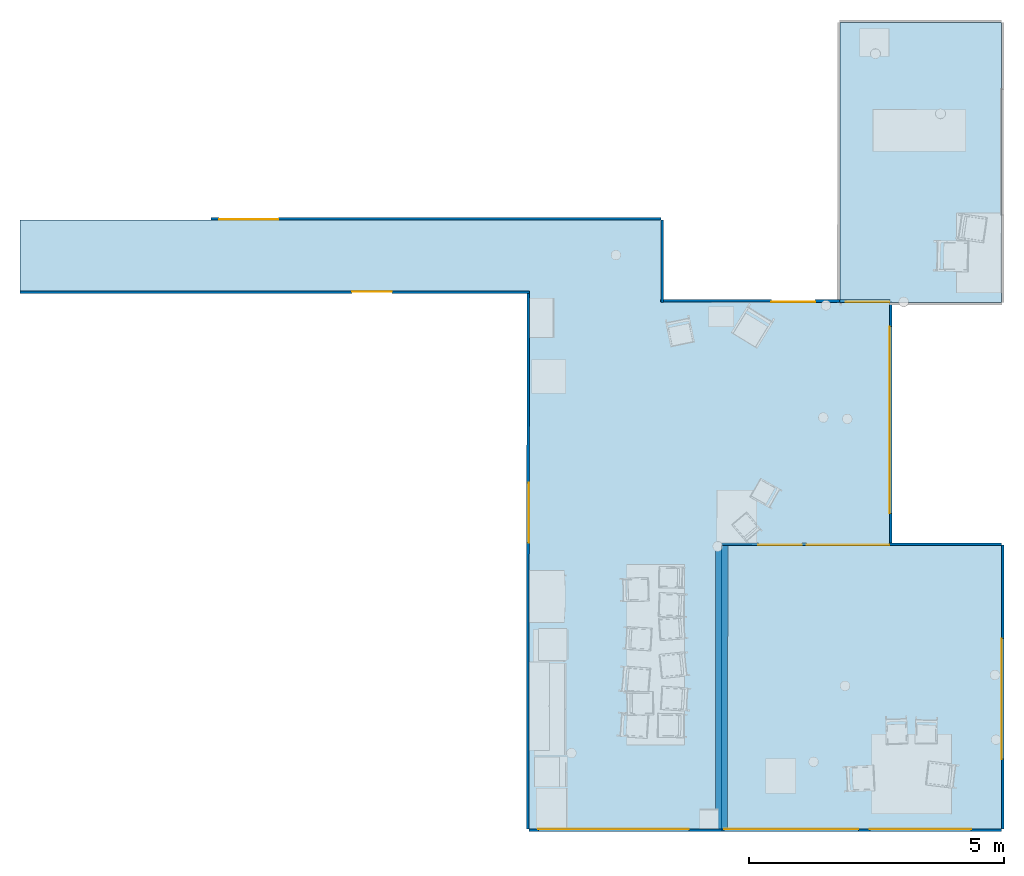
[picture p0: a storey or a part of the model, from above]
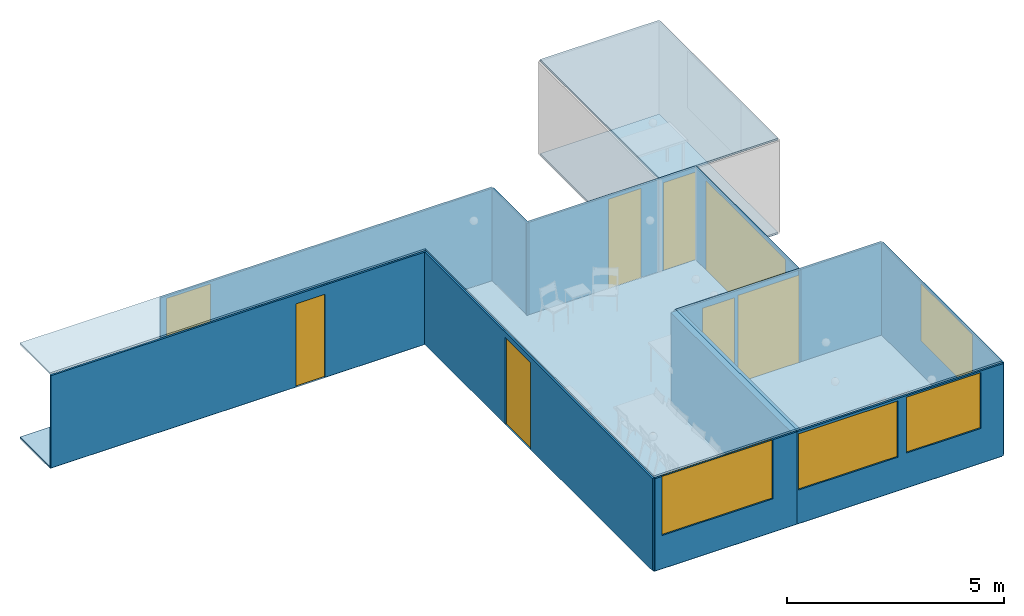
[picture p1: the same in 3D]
Properties of the parts of a building model (IFC2X3)

# File
Description: ViewDefinition [CoordinationView]
Time: 2024-12-10T11:10:35
Written by: IfcOpenShell v0.7.0-f7c03db75
Made in: INDUSTRY_FOUNDATION_CLASSES_2X3

# IfcSite, Site
RefLatitude: 47, 43, 37; RefLongitude: 13, 5, 9; RefElevation: 439.971 m
MetaroomProperties - NorthHeading: (0.999, -0.05, 0.0); UpVector: (0.0, 0.0, 1.0); IsLeftHandedCoordinateSystem: no

# IfcBuilding, Building
Pset_BuildingCommon - NumberOfStoreys: 1

# IfcBuildingStorey, Story 0
In: Building
Elevation: 5.96046e-08 m
Pset_BuildingStoreyCommon - EntranceLevel: no; GrossPlannedArea: 0; NetPlannedArea: 0
Qto_BuildingStoreyBaseQuantities - GrossHeight: 2.60181 m; NetHeight: 2.60181 m; GrossPerimeter: 0 m; GrossFloorArea: 0 m2; NetFloorArea: 0 m2; GrossVolume: 0; NetVolume: 0

# IfcSpace (3)
In: Story 0
Type - PredefinedType: USERDEFINED
InteriorOrExteriorSpace: INTERNAL
Name
001
002
003

# IfcDoor (6)
In: Story 0
Type - ParameterTakesPrecedence: no; Sizeable: no
Type - IfcDoorLiningProperties - LiningDepth: 0.025 m; LiningThickness: 0.1 m
Name | OverallHeight (m) | OverallWidth (m)
Door | 2.46482 | 0.856635
Door | 2.42267 | 0.853935
Door | 2.44985 | 1.17636
Door | 2.51458 | 0.858614
Door | 2.34356 | 0.781152
Door | 2.53363 | 1.16308

# IfcFurnishingElement: Chair (21)
Type - ElementType: Chair
Name | In
2 x Chair | 001
4 x Chair | 002
15 x Chair | 003

# IfcFurnishingElement: Oven
In: 003
Type - ElementType: Oven

# IfcFurnishingElement: Refrigerator
In: 003
Type - ElementType: Refrigerator

# IfcFurnishingElement: Storage (7)
In: 003
Type - ElementType: Storage

# IfcFurnishingElement: Stove
In: 003
Type - ElementType: Stove

# IfcFurnishingElement: Table (9)
Type - ElementType: Table
Name | In
3 x Table | 001
2 x Table | 002
4 x Table | 003

# IfcOpeningElement: OPENING (13)
In: Story 0
Qto_OpeningElementBaseQuantities - Volume: 0
Name | Width (m) | Height (m) | Perimeter (m) | Area (m2)
OpeningElement | 1.61101 | 2.46483 | 8.15167 | 3.97085
OpeningElement | 0.856635 | 2.46482 | 6.64292 | 2.11145
OpeningElement | 2.42267 | 0.853935 | 6.55321 | 2.0688
OpeningElement | 1.6242 | 2.45763 | 8.16364 | 3.99166
OpeningElement | 2.37027 | 1.61371 | 7.96796 | 3.82493
OpeningElement | 2.63991 | 1.58552 | 8.45085 | 4.18562
OpeningElement | 1.98588 | 1.57631 | 7.12438 | 3.13037
OpeningElement | 1.17636 | 2.44985 | 7.25241 | 2.8819
OpeningElement | 0.858614 | 2.51458 | 6.74639 | 2.15906
OpeningElement | 2.34356 | 0.781152 | 6.24942 | 1.83067
OpeningElement | 1.16308 | 2.53363 | 7.39342 | 2.94682
OpeningElement | 2.95581 | 1.66443 | 9.24049 | 4.91976
OpeningElement | 3.66516 | 2.51911 | 12.3685 | 9.23292

# IfcSlab (3)
In: Story 0
Type - PredefinedType: ROOF

# IfcSlab: Floor:Floor-Grnd-Susp_65Scr-80Ins-100Blk-75PC (3)
In: Story 0
Type - PredefinedType: FLOOR

# IfcWallStandardCase (18)
In: Story 0
Type - PredefinedType: STANDARD
Pset_WallCommon - IsExternal: no; ExtendToStructure: yes
Qto_WallBaseQuantities - Width: 0 m; GrossSideArea: 0 m2; NetSideArea: 0 m2; GrossVolume: 0; NetVolume: 0; GrossWeight: 0; NetWeight: 0
Name | Length (m) | Height (m) | GrossFootprintArea (m2) | NetFootprintArea (m2)
Wall | 5.50367 | 2.60181 | 14.3195 | 10.3486
Wall | 2.60181 | 2.21662 | 5.76721 | 5.76721
Wall | 3.18327 | 2.60181 | 8.28226 | 8.28226
Wall | 2.60181 | 0.996655 | 2.5931 | 0.48165
Wall | 5.51351 | 2.60181 | 14.3451 | 14.3451
Wall | 3.31411 | 2.60181 | 8.62268 | 2.56221
Wall | 2.60181 | 2.21094 | 5.75244 | 5.75244
Wall | 5.57758 | 2.60181 | 14.5118 | 10.6868
Wall | 5.56758 | 2.60181 | 14.4858 | 14.4858
Wall | 5.50505 | 2.60181 | 14.3231 | 7.00709
Wall | 0.0472911 | 2.60181 | 0.123042 | 0.123042
Wall | 1.62249 | 2.60181 | 4.22141 | 4.22141
Wall | 10.5692 | 2.60181 | 27.4989 | 24.617
Wall | 3.52492 | 2.60181 | 9.17116 | 7.0121
Wall | 10.0087 | 2.60181 | 26.0408 | 24.2101
Wall | 8.84155 | 2.60181 | 23.004 | 20.0572
Wall | 3.78889 | 2.60181 | 9.85796 | 4.9382
Wall | 4.78531 | 2.60181 | 12.4504 | 3.21751

# IfcWindow (7)
In: Story 0
Type - ConstructionType: ALUMINIUM; OperationType: SINGLE_PANEL; ParameterTakesPrecedence: yes; Sizeable: yes
Type - IfcWindowLiningProperties - LiningDepth: 0.025 m; LiningThickness: 0.1 m
OverallHeight: 1.5 m; OverallWidth: 0.5 m
